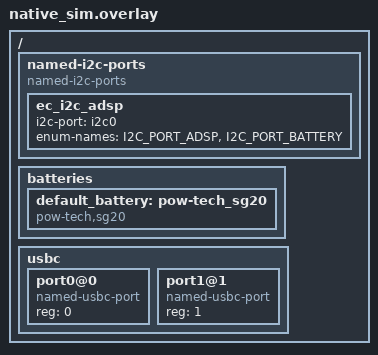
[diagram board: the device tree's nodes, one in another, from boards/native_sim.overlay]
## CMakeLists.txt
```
# Copyright 2026 The ChromiumOS Authors
# Use of this source code is governed by a BSD-style license that can be
# found in the LICENSE file.

cmake_minimum_required(VERSION 3.13.1)
find_package(Zephyr REQUIRED HINTS "${ZEPHYR_BASE}")
project(adsp_comms)

add_subdirectory(${PLATFORM_EC}/zephyr/test/test_utils test_utils)

zephyr_include_directories(
	"${PLATFORM_EC}/include"
	"${PLATFORM_EC}/zephyr/include"
	"${PLATFORM_EC}/zephyr/subsys/adsp_comms"
	"${CMAKE_CURRENT_SOURCE_DIR}/src"
)

zephyr_compile_definitions(CONFIG_TEST_DISABLE_INLINE_CHIPSET_IN_STATE)

target_sources(app PRIVATE
	src/stubs.c
	src/test_adsp_i2c_mode.c
	src/test_adsp_comms.c
)
```

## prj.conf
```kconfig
# Copyright 2026 The ChromiumOS Authors
# Use of this source code is governed by a BSD-style license that can be
# found in the LICENSE file.

CONFIG_ZTEST=y
CONFIG_ZTEST_ASSERT_VERBOSE=1
CONFIG_ZTEST_MOCKING=y
CONFIG_TEST=y
CONFIG_ASSERT=y

CONFIG_SYS_CLOCK_TICKS_PER_SEC=10000
CONFIG_TASKS_SET_TEST_RUNNER_TID_RULE=y

CONFIG_SHELL_BACKEND_DUMMY=y
CONFIG_SHELL_BACKEND_SERIAL=n
CONFIG_SERIAL=y

CONFIG_PLATFORM_EC=y
CONFIG_CROS_EC=y
CONFIG_SHIMMED_TASKS=y
CONFIG_PLATFORM_EC_HOOKS=y
CONFIG_EMUL=y

CONFIG_I2C=y
CONFIG_I2C_TARGET=y

CONFIG_PLATFORM_EC_BATTERY=y
CONFIG_PLATFORM_EC_BATTERY_SMART=y
CONFIG_PLATFORM_EC_BATTERY_STATUS_CUSTOM=y
CONFIG_PLATFORM_EC_BATTERY_PRESENT_NONE=y

CONFIG_PLATFORM_EC_USBC=n
CONFIG_PLATFORM_EC_USB_POWER_DELIVERY=n
CONFIG_PLATFORM_EC_CHARGER=n

CONFIG_PLATFORM_EC_CHARGER_SENSE_RESISTOR=10
CONFIG_PLATFORM_EC_CHARGER_SENSE_RESISTOR_AC=10

CONFIG_PLATFORM_EC_ADSP_CHARGE_MANAGER=y
CONFIG_PLATFORM_EC_CHARGE_CONTROL_PERSIST_TO_BBRAM=y

CONFIG_ADSP_COMMS_STACK_SIZE=2048
CONFIG_ADSP_COMMS_MSGQ_SIZE=16
CONFIG_ADSP_COMMS_PRIORITY=5
```

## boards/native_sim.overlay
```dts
/* Copyright 2026 The ChromiumOS Authors
 * Use of this source code is governed by a BSD-style license that can be
 * found in the LICENSE file.
 */

#include <board-overlays/native_sim.dts>

/ {
	named-i2c-ports {
		compatible = "named-i2c-ports";

		ec_i2c_adsp: ec_i2c_adsp {
			i2c-port = <&i2c0>;
			enum-names = "I2C_PORT_ADSP", "I2C_PORT_BATTERY";
		};
	};

	batteries {
		default_battery: pow-tech_sg20 {
			compatible = "pow-tech,sg20", "battery-smart";
		};
	};

	usbc {
		#address-cells = <1>;
		#size-cells = <0>;

		port0@0 {
			compatible = "named-usbc-port";
			reg = <0>;
		};
		port1@1 {
			compatible = "named-usbc-port";
			reg = <1>;
		};
	};
};
```

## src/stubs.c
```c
/* Copyright 2026 The ChromiumOS Authors
 * Use of this source code is governed by a BSD-style license that can be
 * found in the LICENSE file.
 */

#include "stubs.h"

#include <string.h>

DEFINE_FAKE_VALUE_FUNC(int, chipset_in_state, int);
DEFINE_FAKE_VALUE_FUNC(int, extpower_is_present);
DEFINE_FAKE_VALUE_FUNC(enum battery_present, battery_is_present);
DEFINE_FAKE_VALUE_FUNC(int, sb_read, int, int *);

void stubs_reset(void)
{
	RESET_FAKE(chipset_in_state);
	RESET_FAKE(extpower_is_present);
	RESET_FAKE(battery_is_present);
	RESET_FAKE(sb_read);
	battery_set_fake_soc(-1);
}
```

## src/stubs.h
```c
/* Copyright 2026 The ChromiumOS Authors
 * Use of this source code is governed by a BSD-style license that can be
 * found in the LICENSE file.
 */

#ifndef __TEST_ADSP_COMMS_STUBS_H
#define __TEST_ADSP_COMMS_STUBS_H

#include "battery.h"
#include "battery_smart.h"
#include "chipset.h"
#include "extpower.h"
#include "i2c.h"

#include <zephyr/fff.h>

DECLARE_FAKE_VALUE_FUNC(int, chipset_in_state, int);
DECLARE_FAKE_VALUE_FUNC(int, extpower_is_present);
DECLARE_FAKE_VALUE_FUNC(enum battery_present, battery_is_present);
DECLARE_FAKE_VALUE_FUNC(int, sb_read, int, int *);

void stubs_reset(void);

#endif /* __TEST_ADSP_COMMS_STUBS_H */
```

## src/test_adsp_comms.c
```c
/* Copyright 2026 The ChromiumOS Authors
 * Use of this source code is governed by a BSD-style license that can be
 * found in the LICENSE file.
 */

#include "adsp_comms.h"
#include "battery.h"
#include "battery_smart.h"
#include "charge_manager.h"
#include "charge_state.h"
#include "chipset.h"
#include "console.h"
#include "extpower.h"
#include "hooks.h"
#include "stubs.h"

#include <zephyr/drivers/i2c.h>
#include <zephyr/kernel.h>
#include <zephyr/shell/shell.h>
#include <zephyr/ztest.h>

extern struct i2c_target_config target_cfg;

static void send_adsp_msg(uint8_t fid, uint8_t addr, uint16_t data)
{
	target_cfg.callbacks->write_requested(&target_cfg);
	target_cfg.callbacks->write_received(&target_cfg, addr);
	target_cfg.callbacks->write_received(&target_cfg, fid);
	target_cfg.callbacks->write_received(&target_cfg,
					     (uint8_t)(data & 0xFF));
	target_cfg.callbacks->write_received(&target_cfg, (uint8_t)(data >> 8));
	target_cfg.callbacks->stop(&target_cfg);
	k_msleep(10);
}

static int custom_sb_read(int cmd, int *data)
{
	if (cmd == SB_BATTERY_STATUS) {
		*data = 0x1234;
		return EC_SUCCESS;
	}
	return EC_ERROR_UNKNOWN;
}

static int test_custom_cb_called;
static uint16_t test_custom_cb_data;

static void test_custom_cb(uint8_t fid, uint8_t addr, uint16_t data)
{
	test_custom_cb_called++;
	test_custom_cb_data = data;
}
ADSP_COMMS_REGISTER_CB(ADSP_FEATURE_DEFAULT, ADSP_POWER_STATE_REG_RESTART,
		       test_custom_cb);

static void test_before(void *fixture)
{
	stubs_reset();
	test_custom_cb_called = 0;
	test_custom_cb_data = 0;
	hook_notify(HOOK_CHIPSET_SHUTDOWN_COMPLETE);
}

/* Test active charge port tracking from ADSP OEM messages */
ZTEST_USER(adsp_comms, test_charge_manager_get_active_charge_port)
{
	zassert_equal(charge_manager_get_active_charge_port(),
		      CHARGE_PORT_NONE);

	/* Set charge port 0 (USB0) */
	send_adsp_msg(ADSP_FEATURE_OEM_CUSTOM, ADSP_OEM_CUSTOM_REG_CHARGE_PORT,
		      1);
	zassert_equal(charge_manager_get_active_charge_port(), 0);

	/* Set charge port 1 (USB1) */
	send_adsp_msg(ADSP_FEATURE_OEM_CUSTOM, ADSP_OEM_CUSTOM_REG_CHARGE_PORT,
		      2);
	zassert_equal(charge_manager_get_active_charge_port(), 1);

	/* Disable charging */
	send_adsp_msg(ADSP_FEATURE_OEM_CUSTOM, ADSP_OEM_CUSTOM_REG_CHARGE_PORT,
		      ADSP_OEM_CUSTOM_CHARGE_PORT_DISABLED);
	zassert_equal(charge_manager_get_active_charge_port(),
		      CHARGE_PORT_NONE);

	/* Invalid charge port */
	send_adsp_msg(ADSP_FEATURE_OEM_CUSTOM, ADSP_OEM_CUSTOM_REG_CHARGE_PORT,
		      99);
	zassert_equal(charge_manager_get_active_charge_port(),
		      CHARGE_PORT_NONE);
}

/* Test LED power state machine transitions with and without AC power */
ZTEST_USER(adsp_comms, test_led_pwr_get_state)
{
	/* With AC present */
	extpower_is_present_fake.return_val = 1;

	send_adsp_msg(ADSP_FEATURE_OEM_CUSTOM, ADSP_OEM_CUSTOM_REG_CHARGE_STATE,
		      ADSP_OEM_CUSTOM_CHARGE_STATE_CHARGE);
	zassert_equal(led_pwr_get_state(), LED_PWRS_CHARGE);

	send_adsp_msg(ADSP_FEATURE_OEM_CUSTOM, ADSP_OEM_CUSTOM_REG_CHARGE_STATE,
		      ADSP_OEM_CUSTOM_CHARGE_STATE_DISCHARGE);
	zassert_equal(led_pwr_get_state(), LED_PWRS_DISCHARGE);

	send_adsp_msg(ADSP_FEATURE_OEM_CUSTOM, ADSP_OEM_CUSTOM_REG_CHARGE_STATE,
		      ADSP_OEM_CUSTOM_CHARGE_STATE_ERROR);
	zassert_equal(led_pwr_get_state(), LED_PWRS_ERROR);

	send_adsp_msg(ADSP_FEATURE_OEM_CUSTOM, ADSP_OEM_CUSTOM_REG_CHARGE_STATE,
		      ADSP_OEM_CUSTOM_CHARGE_STATE_IDLE);
	zassert_equal(led_pwr_get_state(), LED_PWRS_IDLE);

	send_adsp_msg(ADSP_FEATURE_OEM_CUSTOM, ADSP_OEM_CUSTOM_REG_CHARGE_STATE,
		      ADSP_OEM_CUSTOM_CHARGE_STATE_FORCED_IDLE);
	zassert_equal(led_pwr_get_state(), LED_PWRS_FORCED_IDLE);

	send_adsp_msg(ADSP_FEATURE_OEM_CUSTOM, ADSP_OEM_CUSTOM_REG_CHARGE_STATE,
		      ADSP_OEM_CUSTOM_CHARGE_STATE_NEAR_FULL);
	zassert_equal(led_pwr_get_state(), LED_PWRS_CHARGE_NEAR_FULL);

	/* Invalid state: remains unchanged */
	send_adsp_msg(ADSP_FEATURE_OEM_CUSTOM, ADSP_OEM_CUSTOM_REG_CHARGE_STATE,
		      99);
	zassert_equal(led_pwr_get_state(), LED_PWRS_CHARGE_NEAR_FULL);

	/* Without AC present: error remains error, other states become
	 * DISCHARGE */
	extpower_is_present_fake.return_val = 0;

	send_adsp_msg(ADSP_FEATURE_OEM_CUSTOM, ADSP_OEM_CUSTOM_REG_CHARGE_STATE,
		      ADSP_OEM_CUSTOM_CHARGE_STATE_ERROR);
	zassert_equal(led_pwr_get_state(), LED_PWRS_ERROR);

	send_adsp_msg(ADSP_FEATURE_OEM_CUSTOM, ADSP_OEM_CUSTOM_REG_CHARGE_STATE,
		      ADSP_OEM_CUSTOM_CHARGE_STATE_IDLE);
	zassert_equal(led_pwr_get_state(), LED_PWRS_DISCHARGE);

	send_adsp_msg(ADSP_FEATURE_OEM_CUSTOM, ADSP_OEM_CUSTOM_REG_CHARGE_STATE,
		      ADSP_OEM_CUSTOM_CHARGE_STATE_CHARGE);
	zassert_equal(led_pwr_get_state(), LED_PWRS_DISCHARGE);
}

/* Test battery status reporting in ON and OFF chipset states */
ZTEST_USER(adsp_comms, test_battery_status)
{
	int status = 0;

	/* Chipset ANY_OFF: reads via sb_read */
	chipset_in_state_fake.return_val = 1;
	sb_read_fake.custom_fake = custom_sb_read;

	zassert_equal(battery_status(&status), EC_SUCCESS);
	zassert_equal(status, 0x1234);

	sb_read_fake.custom_fake = NULL;
	sb_read_fake.return_val = EC_ERROR_UNKNOWN;
	zassert_equal(battery_status(&status), EC_ERROR_UNKNOWN);

	/* Chipset ON: returns active_battery_status */
	chipset_in_state_fake.return_val = 0;

	send_adsp_msg(ADSP_FEATURE_OEM_CUSTOM,
		      ADSP_OEM_CUSTOM_REG_BATTERY_STATE, 0x5678);

	zassert_equal(battery_status(&status), EC_SUCCESS);
	zassert_equal(status, 0x5678);
}

/* Test dispatching of various ADSP feature message callbacks */
ZTEST_USER(adsp_comms, test_adsp_callbacks)
{
	/* Custom registered callback invocation check */
	test_custom_cb_called = 0;
	test_custom_cb_data = 0;
	send_adsp_msg(ADSP_FEATURE_DEFAULT, ADSP_POWER_STATE_REG_RESTART,
		      0x5AA5);
	zassert_equal(test_custom_cb_called, 1);
	zassert_equal(test_custom_cb_data, 0x5AA5);

	/* Power state logging callback */
	send_adsp_msg(ADSP_FEATURE_DEFAULT, ADSP_POWER_STATE_REG_VAL, 0x1000);

	/* Magic packet logging callback: valid and invalid */
	send_adsp_msg(ADSP_FEATURE_OEM_CUSTOM, ADSP_OEM_CUSTOM_REG_MAGIC,
		      ADSP_OEM_CUSTOM_MAGIC_VAL);
	send_adsp_msg(ADSP_FEATURE_OEM_CUSTOM, ADSP_OEM_CUSTOM_REG_MAGIC,
		      0x1234);

	/* Version packet logging callback: valid and invalid */
	send_adsp_msg(ADSP_FEATURE_OEM_CUSTOM, ADSP_OEM_CUSTOM_REG_VERSION,
		      ADSP_OEM_CUSTOM_VERSION_1);
	send_adsp_msg(ADSP_FEATURE_OEM_CUSTOM, ADSP_OEM_CUSTOM_REG_VERSION,
		      0x02);

	/* Battery level: valid and invalid */
	send_adsp_msg(ADSP_FEATURE_OEM_CUSTOM,
		      ADSP_OEM_CUSTOM_REG_BATTERY_LEVEL, 75);
	zassert_equal(battery_get_fake_soc(), 75);

	send_adsp_msg(ADSP_FEATURE_OEM_CUSTOM,
		      ADSP_OEM_CUSTOM_REG_BATTERY_LEVEL, 105);
	zassert_equal(battery_get_fake_soc(), 75);
}

/* Test 'chgstate' console command across multiple power and charge states */
ZTEST_USER(adsp_comms, test_command_chgstate)
{
	const struct shell *sh = get_ec_shell();

	extpower_is_present_fake.return_val = 1;
	battery_is_present_fake.return_val = BP_YES;
	battery_set_fake_soc(80);

	/* CHARGE state */
	send_adsp_msg(ADSP_FEATURE_OEM_CUSTOM, ADSP_OEM_CUSTOM_REG_CHARGE_STATE,
		      ADSP_OEM_CUSTOM_CHARGE_STATE_CHARGE);
	zassert_ok(shell_execute_cmd(sh, "chgstate"));

	/* NEAR_FULL state */
	battery_is_present_fake.return_val = BP_NO;
	send_adsp_msg(ADSP_FEATURE_OEM_CUSTOM, ADSP_OEM_CUSTOM_REG_CHARGE_STATE,
		      ADSP_OEM_CUSTOM_CHARGE_STATE_NEAR_FULL);
	zassert_ok(shell_execute_cmd(sh, "chgstate"));

	/* DISCHARGE state */
	battery_is_present_fake.return_val = BP_NOT_SURE;
	extpower_is_present_fake.return_val = 0;
	send_adsp_msg(ADSP_FEATURE_OEM_CUSTOM, ADSP_OEM_CUSTOM_REG_CHARGE_STATE,
		      ADSP_OEM_CUSTOM_CHARGE_STATE_DISCHARGE);
	zassert_ok(shell_execute_cmd(sh, "chgstate"));

	/* FORCED_IDLE state */
	battery_is_present_fake.return_val = BP_YES;
	extpower_is_present_fake.return_val = 1;
	send_adsp_msg(ADSP_FEATURE_OEM_CUSTOM, ADSP_OEM_CUSTOM_REG_CHARGE_STATE,
		      ADSP_OEM_CUSTOM_CHARGE_STATE_FORCED_IDLE);
	zassert_ok(shell_execute_cmd(sh, "chgstate"));
}

/* Test reset of ADSP comms state on HOOK_CHIPSET_SHUTDOWN_COMPLETE */
ZTEST_USER(adsp_comms, test_adsp_comms_shutdown_reset)
{
	int status = 0;

	/* Setup active values */
	battery_set_fake_soc(50);
	send_adsp_msg(ADSP_FEATURE_OEM_CUSTOM, ADSP_OEM_CUSTOM_REG_CHARGE_PORT,
		      1);
	send_adsp_msg(ADSP_FEATURE_OEM_CUSTOM, ADSP_OEM_CUSTOM_REG_CHARGE_STATE,
		      ADSP_OEM_CUSTOM_CHARGE_STATE_CHARGE);
	send_adsp_msg(ADSP_FEATURE_OEM_CUSTOM,
		      ADSP_OEM_CUSTOM_REG_BATTERY_STATE, 0x1111);

	zassert_equal(battery_get_fake_soc(), 50);
	zassert_equal(charge_manager_get_active_charge_port(), 0);

	/* Trigger shutdown reset hook */
	hook_notify(HOOK_CHIPSET_SHUTDOWN_COMPLETE);

	zassert_equal(battery_get_fake_soc(), -1);
	zassert_equal(charge_manager_get_active_charge_port(),
		      CHARGE_PORT_NONE);

	extpower_is_present_fake.return_val = 1;
	zassert_equal(led_pwr_get_state(), LED_PWRS_IDLE);

	chipset_in_state_fake.return_val = 0;
	zassert_equal(battery_status(&status), EC_SUCCESS);
	zassert_equal(status, 0);
}

ZTEST_SUITE(adsp_comms, NULL, NULL, test_before, NULL, NULL);
```

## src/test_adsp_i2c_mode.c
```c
/* Copyright 2026 The ChromiumOS Authors
 * Use of this source code is governed by a BSD-style license that can be
 * found in the LICENSE file.
 */

#include "adsp_comms.h"
#include "battery.h"
#include "charge_manager.h"
#include "chipset.h"
#include "hooks.h"
#include "i2c.h"
#include "stubs.h"
#include "system.h"

#include <zephyr/drivers/i2c.h>
#include <zephyr/kernel.h>
#include <zephyr/ztest.h>

extern struct i2c_target_config target_cfg;
void board_chipset_startup_i2c_target(void);
void board_chipset_shutdown_complete_i2c_controller(void);

/*
 * Note on I2C target mode assertions:
 * In the emulated I2C driver (i2c_emul.c), i2c_target_unregister(dev, cfg)
 * returns 0 when cfg is currently registered as the active target, and -EINVAL
 * when it is not registered (i.e. controller mode is active). This is used in
 * the tests below to verify target vs controller state transitions.
 */

static void test_before(void *fixture)
{
	stubs_reset();
}

/* Test I2C target read callbacks return default 0xFF response */
ZTEST_USER(adsp_i2c_mode, test_target_callbacks_read)
{
	uint8_t val = 0;

	zassert_not_null(target_cfg.callbacks);
	zassert_not_null(target_cfg.callbacks->read_requested);
	zassert_not_null(target_cfg.callbacks->read_processed);

	zassert_equal(target_cfg.callbacks->read_requested(&target_cfg, &val),
		      0);
	zassert_equal(val, 0xFF);

	val = 0;
	zassert_equal(target_cfg.callbacks->read_processed(&target_cfg, &val),
		      0);
	zassert_equal(val, 0xFF);
}

/* Test I2C target write byte accumulation and buffer overflow handling */
ZTEST_USER(adsp_i2c_mode, test_target_callbacks_write_and_overflow)
{
	zassert_not_null(target_cfg.callbacks);
	zassert_not_null(target_cfg.callbacks->write_requested);
	zassert_not_null(target_cfg.callbacks->write_received);

	zassert_equal(target_cfg.callbacks->write_requested(&target_cfg), 0);

	/* 4 valid bytes */
	zassert_equal(target_cfg.callbacks->write_received(&target_cfg, 0x01),
		      0);
	zassert_equal(target_cfg.callbacks->write_received(&target_cfg, 0x02),
		      0);
	zassert_equal(target_cfg.callbacks->write_received(&target_cfg, 0x03),
		      0);
	zassert_equal(target_cfg.callbacks->write_received(&target_cfg, 0x04),
		      0);

	/* 5th byte should overflow and return -ENOMEM */
	zassert_equal(target_cfg.callbacks->write_received(&target_cfg, 0x05),
		      -ENOMEM);
}

/* Test I2C target stop callback processing for empty, partial, and full packets
 */
ZTEST_USER(adsp_i2c_mode, test_target_callbacks_stop)
{
	zassert_not_null(target_cfg.callbacks->stop);

	/* Stop with 0 bytes */
	zassert_equal(target_cfg.callbacks->write_requested(&target_cfg), 0);
	zassert_equal(target_cfg.callbacks->stop(&target_cfg), 0);

	/* Stop with incomplete packet (e.g. 2 bytes) */
	zassert_equal(target_cfg.callbacks->write_requested(&target_cfg), 0);
	zassert_equal(target_cfg.callbacks->write_received(
			      &target_cfg, ADSP_OEM_CUSTOM_REG_MAGIC),
		      0);
	zassert_equal(target_cfg.callbacks->write_received(
			      &target_cfg, ADSP_FEATURE_OEM_CUSTOM),
		      0);
	zassert_equal(target_cfg.callbacks->stop(&target_cfg), 0);

	/* Stop with full 4-byte packet */
	zassert_equal(target_cfg.callbacks->write_requested(&target_cfg), 0);
	zassert_equal(target_cfg.callbacks->write_received(
			      &target_cfg, ADSP_OEM_CUSTOM_REG_MAGIC),
		      0);
	zassert_equal(target_cfg.callbacks->write_received(
			      &target_cfg, ADSP_FEATURE_OEM_CUSTOM),
		      0);
	zassert_equal(target_cfg.callbacks->write_received(
			      &target_cfg, ADSP_OEM_CUSTOM_MAGIC_VAL),
		      0);
	zassert_equal(target_cfg.callbacks->write_received(&target_cfg, 0x00),
		      0);
	zassert_equal(target_cfg.callbacks->stop(&target_cfg), 0);

	k_msleep(10);
}

/* Test ADSP message queue full condition when incoming packets exceed capacity
 */
ZTEST(adsp_i2c_mode, test_target_callbacks_queue_full)
{
	/* Fill message queue to trigger queue full branch */
	for (int i = 0; i < CONFIG_ADSP_COMMS_MSGQ_SIZE + 5; i++) {
		zassert_equal(
			target_cfg.callbacks->write_requested(&target_cfg), 0);
		zassert_equal(target_cfg.callbacks->write_received(
				      &target_cfg, ADSP_OEM_CUSTOM_REG_MAGIC),
			      0);
		zassert_equal(target_cfg.callbacks->write_received(
				      &target_cfg, ADSP_FEATURE_OEM_CUSTOM),
			      0);
		zassert_equal(target_cfg.callbacks->write_received(
				      &target_cfg, ADSP_OEM_CUSTOM_MAGIC_VAL),
			      0);
		zassert_equal(target_cfg.callbacks->write_received(&target_cfg,
								   0x00),
			      0);
		zassert_equal(target_cfg.callbacks->stop(&target_cfg), 0);
	}

	k_msleep(20);
}

/* Test processing of messages with unhandled feature IDs and register addresses
 */
ZTEST_USER(adsp_i2c_mode, test_unhandled_callback)
{
	zassert_equal(charge_manager_get_active_charge_port(),
		      CHARGE_PORT_NONE);
	zassert_equal(battery_get_fake_soc(), -1);

	/* Send message with unhandled fid and addr */
	zassert_equal(target_cfg.callbacks->write_requested(&target_cfg), 0);
	zassert_equal(target_cfg.callbacks->write_received(&target_cfg, 0xAA),
		      0);
	zassert_equal(target_cfg.callbacks->write_received(&target_cfg, 0xBB),
		      0);
	zassert_equal(target_cfg.callbacks->write_received(&target_cfg, 0x34),
		      0);
	zassert_equal(target_cfg.callbacks->write_received(&target_cfg, 0x12),
		      0);
	zassert_equal(target_cfg.callbacks->stop(&target_cfg), 0);

	k_msleep(10);

	/* Verify state is unaffected by unhandled callback */
	zassert_equal(charge_manager_get_active_charge_port(),
		      CHARGE_PORT_NONE);
	zassert_equal(battery_get_fake_soc(), -1);
}

/* Test switching ADSP I2C bus to target mode on chipset startup */
ZTEST_USER(adsp_i2c_mode, test_board_chipset_startup_i2c_target)
{
	const struct device *i2c_dev = i2c_get_device_for_port(I2C_PORT_ADSP);

	zassert_not_null(i2c_dev);

	/* Ensure starting from controller mode */
	board_chipset_shutdown_complete_i2c_controller();
	zassert_not_equal(i2c_target_unregister(i2c_dev, &target_cfg), 0);

	/* Success path: switches to target mode */
	board_chipset_startup_i2c_target();
	zassert_ok(i2c_target_unregister(i2c_dev, &target_cfg));

	/* Re-register target and test error path / redundant call */
	board_chipset_startup_i2c_target();
	board_chipset_startup_i2c_target();

	/* Revert to controller mode */
	board_chipset_shutdown_complete_i2c_controller();
	zassert_not_equal(i2c_target_unregister(i2c_dev, &target_cfg), 0);

	/* Hook notification */
	hook_notify(HOOK_CHIPSET_STARTUP);
	zassert_ok(i2c_target_unregister(i2c_dev, &target_cfg));
	zassert_not_equal(atomic_get(&sleep_mask) & SLEEP_MASK_I2C_PERIPHERAL,
			  0);

	board_chipset_startup_i2c_target();
	hook_notify(HOOK_CHIPSET_SHUTDOWN_COMPLETE);
	zassert_not_equal(i2c_target_unregister(i2c_dev, &target_cfg), 0);
	zassert_equal(atomic_get(&sleep_mask) & SLEEP_MASK_I2C_PERIPHERAL, 0);
}

/* Test initialization of ADSP I2C bus mode on HOOK_INIT for ON and OFF states
 */
ZTEST_USER(adsp_i2c_mode, test_adsp_i2c_init)
{
	const struct device *i2c_dev = i2c_get_device_for_port(I2C_PORT_ADSP);

	zassert_not_null(i2c_dev);

	/* Ensure starting from controller mode */
	board_chipset_shutdown_complete_i2c_controller();

	/* When chipset is in ON state, HOOK_INIT configures as target */
	chipset_in_state_fake.return_val = 1;
	hook_notify(HOOK_INIT);
	zassert_equal(chipset_in_state_fake.call_count, 1);
	zassert_equal(chipset_in_state_fake.arg0_val, CHIPSET_STATE_ON);
	/* Target is now registered, unregistering directly should succeed */
	zassert_ok(i2c_target_unregister(i2c_dev, &target_cfg));

	/*
	 * When chipset is not in ON state (adsp_i2c_init specifically queries
	 * CHIPSET_STATE_ON, so verify the query and that target mode is not
	 * enabled)
	 */
	RESET_FAKE(chipset_in_state);
	chipset_in_state_fake.return_val = 0;
	hook_notify(HOOK_INIT);
	zassert_equal(chipset_in_state_fake.call_count, 1);
	zassert_equal(chipset_in_state_fake.arg0_val, CHIPSET_STATE_ON);
	/* Target was not registered, unregistering should fail */
	zassert_not_equal(i2c_target_unregister(i2c_dev, &target_cfg), 0);
}

/* Test switching ADSP I2C bus back to controller mode on chipset shutdown */
ZTEST_USER(adsp_i2c_mode, test_board_chipset_shutdown_complete_i2c_controller)
{
	const struct device *i2c_dev = i2c_get_device_for_port(I2C_PORT_ADSP);

	zassert_not_null(i2c_dev);

	/* Success path: register first then shutdown */
	board_chipset_startup_i2c_target();
	board_chipset_shutdown_complete_i2c_controller();
	zassert_not_equal(i2c_target_unregister(i2c_dev, &target_cfg), 0);

	/* Error path: unregister when not registered fails gracefully */
	board_chipset_shutdown_complete_i2c_controller();
	zassert_not_equal(i2c_target_unregister(i2c_dev, &target_cfg), 0);
}

ZTEST_SUITE(adsp_i2c_mode, NULL, NULL, test_before, NULL, NULL);
```
